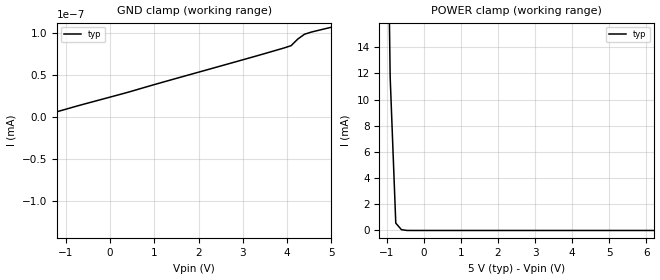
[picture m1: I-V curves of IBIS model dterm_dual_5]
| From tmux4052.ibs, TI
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| dterm_dual_5
[Model]   dterm_dual_5
Model_type   Terminator
|   typ   min   max
C_comp   6.362683e-12   NA   NA
[Voltage Range]   5   NA   NA
[Temperature Range]   27   NA   NA
[Power Clamp Reference]   5   NA   NA
[GND Clamp Reference]   0   NA   NA
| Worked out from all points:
|   GND clamp passes 1 mA (typ) near -5.76 V on its own axis
|   POWER clamp passes 1 mA (typ) near -0.76 V on its own axis
[GND Clamp]
|   Voltage   I(typ)   I(min)   I(max)
-10V      -3.643A    NA         NA
-5.455V   -30.47nA   NA         NA
-5.303V   -84.49pA   NA         NA
-5.152V   -60.21pA   NA         NA
-4.394V   -48.53pA   NA         NA
-3.939V   -34.13pA   NA         NA
-1.818V   -2.792pA   NA         NA
-1.667V   -5.674pA   NA         NA
-1.515V   1.66pA     NA         NA
3.939V    82.28pA    NA         NA
4.394V    98.48pA    NA         NA
5V        106.8pA    NA         NA
[POWER Clamp]
|   Voltage   I(typ)   I(min)   I(max)
-5V       2.031A     NA         NA
-1.061V   43.91mA    NA         NA
-909.1mV  11.75mA    NA         NA
-757.6mV  561.7uA    NA         NA
-606.1mV  63.16uA    NA         NA
-303mV    751pA      NA         NA
10V       -58.07pA   NA         NA
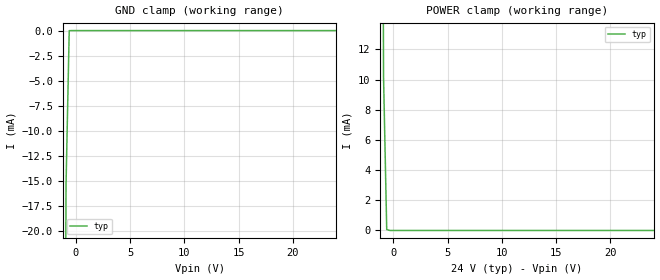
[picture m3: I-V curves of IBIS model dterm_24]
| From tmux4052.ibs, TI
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| dterm_24
[Model]   dterm_24
Model_type   Terminator
|   typ   min   max
C_comp   4.014581e-12   NA   NA
[Voltage Range]   24   NA   NA
[Temperature Range]   27   NA   NA
[Power Clamp Reference]   24   NA   NA
[GND Clamp Reference]   0   NA   NA
[GND Clamp]
|   Voltage   I(typ)   I(min)   I(max)
-5V       -3.643A    NA         NA
-1.192V   -94.86mA   NA         NA
-899mV    -15.33mA   NA         NA
-606.1mV  -5.765uA   NA         NA
24V       256.8pA    NA         NA
[POWER Clamp]
|   Voltage   I(typ)   I(min)   I(max)
-5V       2.031A     NA         NA
-1.192V   78.03mA    NA         NA
-899mV    10.2mA     NA         NA
-606.1mV  63.23uA    NA         NA
-313.1mV  12.07nA    NA         NA
24V       -138.1pA   NA         NA
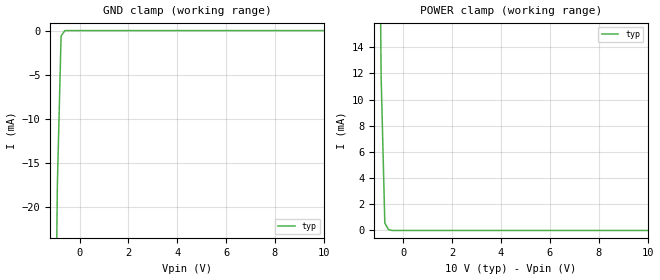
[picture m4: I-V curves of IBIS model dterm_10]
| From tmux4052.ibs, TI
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| dterm_10
[Model]   dterm_10
Model_type   Terminator
|   typ   min   max
C_comp   6.362683e-12   NA   NA
[Voltage Range]   10   NA   NA
[Temperature Range]   27   NA   NA
[Power Clamp Reference]   10   NA   NA
[GND Clamp Reference]   0   NA   NA
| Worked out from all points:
|   GND clamp passes 1 mA (typ) near -0.76 V on its own axis
|   POWER clamp passes 1 mA (typ) near -0.76 V on its own axis
[GND Clamp]
|   Voltage   I(typ)   I(min)   I(max)
-5V       -3.643A    NA         NA
-1.061V   -55.46mA   NA         NA
-909.1mV  -17.41mA   NA         NA
-757.6mV  -623.4uA   NA         NA
-606.1mV  -5.763uA   NA         NA
10V       106.8pA    NA         NA
[POWER Clamp]
|   Voltage   I(typ)   I(min)   I(max)
-5V       2.031A     NA         NA
-1.061V   43.91mA    NA         NA
-909.1mV  11.75mA    NA         NA
-757.6mV  561.7uA    NA         NA
-606.1mV  63.17uA    NA         NA
-303mV    751pA      NA         NA
10V       -58.07pA   NA         NA
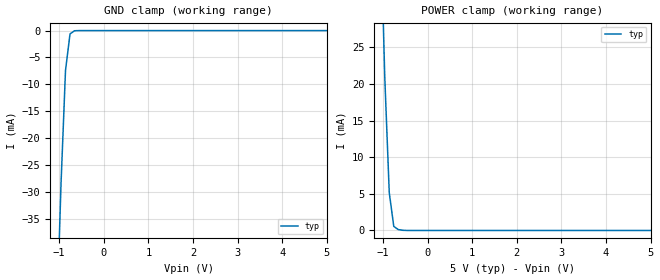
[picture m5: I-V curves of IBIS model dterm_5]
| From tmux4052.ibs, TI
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| dterm_5
[Model]   dterm_5
Model_type   Terminator
|   typ   min   max
C_comp   6.362683e-12   NA   NA
[Voltage Range]   5   NA   NA
[Temperature Range]   27   NA   NA
[Power Clamp Reference]   5   NA   NA
[GND Clamp Reference]   0   NA   NA
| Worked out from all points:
|   GND clamp passes 1 mA (typ) near -0.76 V on its own axis
|   POWER clamp passes 1 mA (typ) near -0.77 V on its own axis
[GND Clamp]
|   Voltage   I(typ)   I(min)   I(max)
-5V       -3.643A    NA         NA
-1.061V   -55.46mA   NA         NA
-959.6mV  -28.6mA    NA         NA
-858.6mV  -7.403mA   NA         NA
-757.6mV  -623.4uA   NA         NA
-656.6mV  -32.47uA   NA         NA
5V        53.43pA    NA         NA
[POWER Clamp]
|   Voltage   I(typ)   I(min)   I(max)
-5V       2.031A     NA         NA
-1.061V   43.91mA    NA         NA
-959.6mV  21mA       NA         NA
-858.6mV  5.169mA    NA         NA
-757.6mV  561.5uA    NA         NA
-656.6mV  120.2uA    NA         NA
-454.6mV  1.693uA    NA         NA
5V        -29.79pA   NA         NA
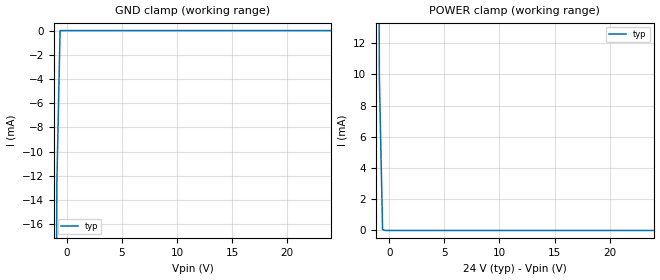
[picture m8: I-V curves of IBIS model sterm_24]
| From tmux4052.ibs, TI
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| sterm_24
[Model]   sterm_24
Model_type   Terminator
|   typ   min   max
C_comp   2.533030e-12   NA   NA
[Voltage Range]   24   NA   NA
[Temperature Range]   27   NA   NA
[Power Clamp Reference]   24   NA   NA
[GND Clamp Reference]   0   NA   NA
[GND Clamp]
|   Voltage   I(typ)   I(min)   I(max)
-5V       -2.321A    NA         NA
-1.192V   -82.36mA   NA         NA
-899mV    -12.7mA    NA         NA
-606.1mV  -5.735uA   NA         NA
24V       256.8pA    NA         NA
[POWER Clamp]
|   Voltage   I(typ)   I(min)   I(max)
-5V       1.914A     NA         NA
-1.192V   76.55mA    NA         NA
-899mV    9.847mA    NA         NA
-606.1mV  57.32uA    NA         NA
-313.1mV  12.07nA    NA         NA
24V       -138.1pA   NA         NA
